VERSION 5.7 ;
  NOWIREEXTENSIONATPIN ON ;
  DIVIDERCHAR "/" ;
  BUSBITCHARS "[]" ;
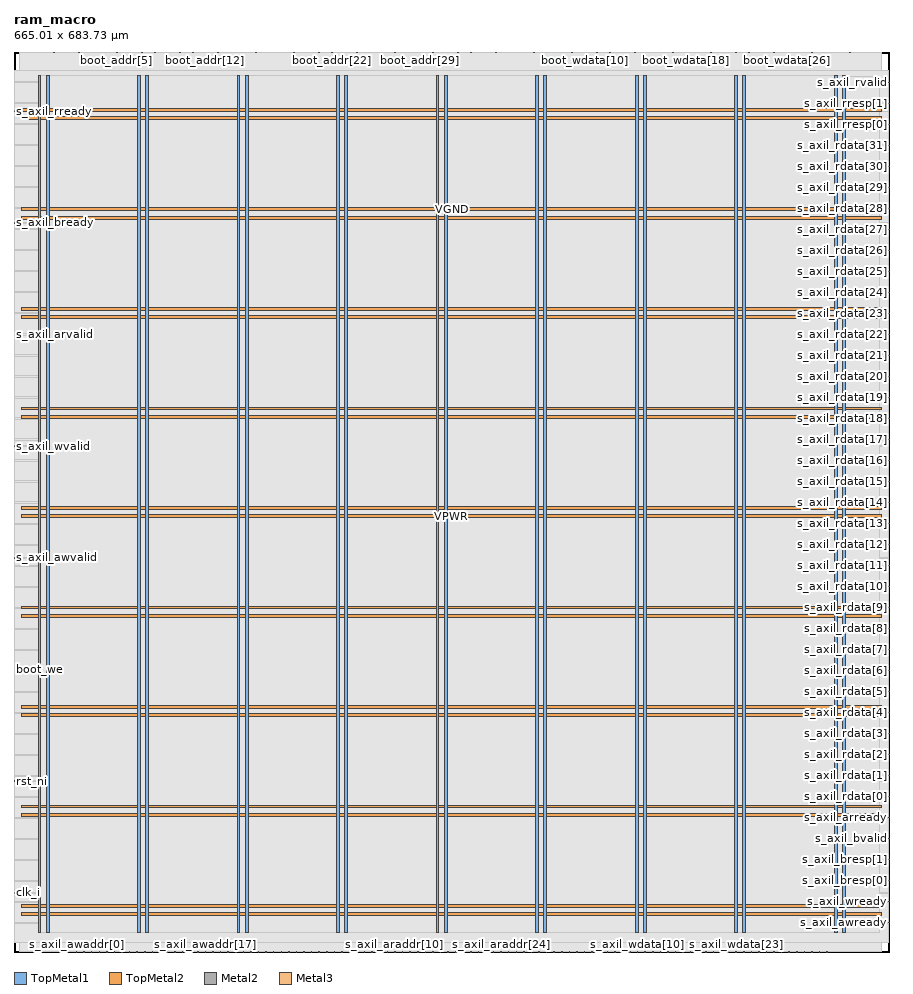
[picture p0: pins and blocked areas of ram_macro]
MACRO ram_macro
  CLASS BLOCK ;
  FOREIGN ram_macro ;
  ORIGIN 0.000 0.000 ;
  SIZE 665.010 BY 683.730 ;
  PIN VGND
    DIRECTION INOUT ;
    USE GROUND ;
    PORT
      LAYER TopMetal1 ;
        RECT 24.460 14.490 26.660 665.910 ;
    END
    PORT
      LAYER TopMetal1 ;
        RECT 100.060 14.490 102.260 665.910 ;
    END
    PORT
      LAYER TopMetal1 ;
        RECT 175.660 14.490 177.860 665.910 ;
    END
    PORT
      LAYER TopMetal1 ;
        RECT 251.260 14.490 253.460 665.910 ;
    END
    PORT
      LAYER TopMetal1 ;
        RECT 326.860 14.490 329.060 665.910 ;
    END
    PORT
      LAYER TopMetal1 ;
        RECT 402.460 14.490 404.660 665.910 ;
    END
    PORT
      LAYER TopMetal1 ;
        RECT 478.060 14.490 480.260 665.910 ;
    END
    PORT
      LAYER TopMetal1 ;
        RECT 553.660 14.490 555.860 665.910 ;
    END
    PORT
      LAYER TopMetal1 ;
        RECT 629.260 14.490 631.460 665.910 ;
    END
    PORT
      LAYER TopMetal2 ;
        RECT 5.760 33.820 659.040 36.020 ;
    END
    PORT
      LAYER TopMetal2 ;
        RECT 5.760 109.420 659.040 111.620 ;
    END
    PORT
      LAYER TopMetal2 ;
        RECT 5.760 185.020 659.040 187.220 ;
    END
    PORT
      LAYER TopMetal2 ;
        RECT 5.760 260.620 659.040 262.820 ;
    END
    PORT
      LAYER TopMetal2 ;
        RECT 5.760 336.220 659.040 338.420 ;
    END
    PORT
      LAYER TopMetal2 ;
        RECT 5.760 411.820 659.040 414.020 ;
    END
    PORT
      LAYER TopMetal2 ;
        RECT 5.760 487.420 659.040 489.620 ;
    END
    PORT
      LAYER TopMetal2 ;
        RECT 5.760 563.020 659.040 565.220 ;
    END
    PORT
      LAYER TopMetal2 ;
        RECT 5.760 638.620 659.040 640.820 ;
    END
  END VGND
  PIN VPWR
    DIRECTION INOUT ;
    USE POWER ;
    PORT
      LAYER TopMetal1 ;
        RECT 18.260 14.900 20.460 665.500 ;
    END
    PORT
      LAYER TopMetal1 ;
        RECT 93.860 14.900 96.060 665.500 ;
    END
    PORT
      LAYER TopMetal1 ;
        RECT 169.460 14.900 171.660 665.500 ;
    END
    PORT
      LAYER TopMetal1 ;
        RECT 245.060 14.900 247.260 665.500 ;
    END
    PORT
      LAYER TopMetal1 ;
        RECT 320.660 14.900 322.860 665.500 ;
    END
    PORT
      LAYER TopMetal1 ;
        RECT 396.260 14.900 398.460 665.500 ;
    END
    PORT
      LAYER TopMetal1 ;
        RECT 471.860 14.900 474.060 665.500 ;
    END
    PORT
      LAYER TopMetal1 ;
        RECT 547.460 14.900 549.660 665.500 ;
    END
    PORT
      LAYER TopMetal1 ;
        RECT 623.060 14.900 625.260 665.500 ;
    END
    PORT
      LAYER TopMetal2 ;
        RECT 5.760 27.620 659.040 29.820 ;
    END
    PORT
      LAYER TopMetal2 ;
        RECT 5.760 103.220 659.040 105.420 ;
    END
    PORT
      LAYER TopMetal2 ;
        RECT 5.760 178.820 659.040 181.020 ;
    END
    PORT
      LAYER TopMetal2 ;
        RECT 5.760 254.420 659.040 256.620 ;
    END
    PORT
      LAYER TopMetal2 ;
        RECT 5.760 330.020 659.040 332.220 ;
    END
    PORT
      LAYER TopMetal2 ;
        RECT 5.760 405.620 659.040 407.820 ;
    END
    PORT
      LAYER TopMetal2 ;
        RECT 5.760 481.220 659.040 483.420 ;
    END
    PORT
      LAYER TopMetal2 ;
        RECT 5.760 556.820 659.040 559.020 ;
    END
    PORT
      LAYER TopMetal2 ;
        RECT 5.760 632.420 659.040 634.620 ;
    END
  END VPWR
  PIN boot_addr[0]
    DIRECTION INPUT ;
    USE SIGNAL ;
    PORT
      LAYER Metal2 ;
        RECT 30.040 683.330 30.440 683.730 ;
    END
  END boot_addr[0]
  PIN boot_addr[10]
    DIRECTION INPUT ;
    USE SIGNAL ;
    ANTENNAGATEAREA 0.180700 ;
    PORT
      LAYER Metal2 ;
        RECT 126.040 683.330 126.440 683.730 ;
    END
  END boot_addr[10]
  PIN boot_addr[11]
    DIRECTION INPUT ;
    USE SIGNAL ;
    ANTENNAGATEAREA 0.180700 ;
    PORT
      LAYER Metal2 ;
        RECT 135.640 683.330 136.040 683.730 ;
    END
  END boot_addr[11]
  PIN boot_addr[12]
    DIRECTION INPUT ;
    USE SIGNAL ;
    PORT
      LAYER Metal2 ;
        RECT 145.240 683.330 145.640 683.730 ;
    END
  END boot_addr[12]
  PIN boot_addr[13]
    DIRECTION INPUT ;
    USE SIGNAL ;
    PORT
      LAYER Metal2 ;
        RECT 154.840 683.330 155.240 683.730 ;
    END
  END boot_addr[13]
  PIN boot_addr[14]
    DIRECTION INPUT ;
    USE SIGNAL ;
    PORT
      LAYER Metal2 ;
        RECT 164.440 683.330 164.840 683.730 ;
    END
  END boot_addr[14]
  PIN boot_addr[15]
    DIRECTION INPUT ;
    USE SIGNAL ;
    PORT
      LAYER Metal2 ;
        RECT 174.040 683.330 174.440 683.730 ;
    END
  END boot_addr[15]
  PIN boot_addr[16]
    DIRECTION INPUT ;
    USE SIGNAL ;
    PORT
      LAYER Metal2 ;
        RECT 183.640 683.330 184.040 683.730 ;
    END
  END boot_addr[16]
  PIN boot_addr[17]
    DIRECTION INPUT ;
    USE SIGNAL ;
    PORT
      LAYER Metal2 ;
        RECT 193.240 683.330 193.640 683.730 ;
    END
  END boot_addr[17]
  PIN boot_addr[18]
    DIRECTION INPUT ;
    USE SIGNAL ;
    PORT
      LAYER Metal2 ;
        RECT 202.840 683.330 203.240 683.730 ;
    END
  END boot_addr[18]
  PIN boot_addr[19]
    DIRECTION INPUT ;
    USE SIGNAL ;
    PORT
      LAYER Metal2 ;
        RECT 212.440 683.330 212.840 683.730 ;
    END
  END boot_addr[19]
  PIN boot_addr[1]
    DIRECTION INPUT ;
    USE SIGNAL ;
    PORT
      LAYER Metal2 ;
        RECT 39.640 683.330 40.040 683.730 ;
    END
  END boot_addr[1]
  PIN boot_addr[20]
    DIRECTION INPUT ;
    USE SIGNAL ;
    PORT
      LAYER Metal2 ;
        RECT 222.040 683.330 222.440 683.730 ;
    END
  END boot_addr[20]
  PIN boot_addr[21]
    DIRECTION INPUT ;
    USE SIGNAL ;
    PORT
      LAYER Metal2 ;
        RECT 231.640 683.330 232.040 683.730 ;
    END
  END boot_addr[21]
  PIN boot_addr[22]
    DIRECTION INPUT ;
    USE SIGNAL ;
    PORT
      LAYER Metal2 ;
        RECT 241.240 683.330 241.640 683.730 ;
    END
  END boot_addr[22]
  PIN boot_addr[23]
    DIRECTION INPUT ;
    USE SIGNAL ;
    PORT
      LAYER Metal2 ;
        RECT 250.840 683.330 251.240 683.730 ;
    END
  END boot_addr[23]
  PIN boot_addr[24]
    DIRECTION INPUT ;
    USE SIGNAL ;
    PORT
      LAYER Metal2 ;
        RECT 260.440 683.330 260.840 683.730 ;
    END
  END boot_addr[24]
  PIN boot_addr[25]
    DIRECTION INPUT ;
    USE SIGNAL ;
    PORT
      LAYER Metal2 ;
        RECT 270.040 683.330 270.440 683.730 ;
    END
  END boot_addr[25]
  PIN boot_addr[26]
    DIRECTION INPUT ;
    USE SIGNAL ;
    PORT
      LAYER Metal2 ;
        RECT 279.640 683.330 280.040 683.730 ;
    END
  END boot_addr[26]
  PIN boot_addr[27]
    DIRECTION INPUT ;
    USE SIGNAL ;
    PORT
      LAYER Metal2 ;
        RECT 289.240 683.330 289.640 683.730 ;
    END
  END boot_addr[27]
  PIN boot_addr[28]
    DIRECTION INPUT ;
    USE SIGNAL ;
    PORT
      LAYER Metal2 ;
        RECT 298.840 683.330 299.240 683.730 ;
    END
  END boot_addr[28]
  PIN boot_addr[29]
    DIRECTION INPUT ;
    USE SIGNAL ;
    PORT
      LAYER Metal2 ;
        RECT 308.440 683.330 308.840 683.730 ;
    END
  END boot_addr[29]
  PIN boot_addr[2]
    DIRECTION INPUT ;
    USE SIGNAL ;
    ANTENNAGATEAREA 0.180700 ;
    PORT
      LAYER Metal2 ;
        RECT 49.240 683.330 49.640 683.730 ;
    END
  END boot_addr[2]
  PIN boot_addr[30]
    DIRECTION INPUT ;
    USE SIGNAL ;
    PORT
      LAYER Metal2 ;
        RECT 318.040 683.330 318.440 683.730 ;
    END
  END boot_addr[30]
  PIN boot_addr[31]
    DIRECTION INPUT ;
    USE SIGNAL ;
    PORT
      LAYER Metal2 ;
        RECT 327.640 683.330 328.040 683.730 ;
    END
  END boot_addr[31]
  PIN boot_addr[3]
    DIRECTION INPUT ;
    USE SIGNAL ;
    ANTENNAGATEAREA 0.180700 ;
    PORT
      LAYER Metal2 ;
        RECT 58.840 683.330 59.240 683.730 ;
    END
  END boot_addr[3]
  PIN boot_addr[4]
    DIRECTION INPUT ;
    USE SIGNAL ;
    ANTENNAGATEAREA 0.180700 ;
    PORT
      LAYER Metal2 ;
        RECT 68.440 683.330 68.840 683.730 ;
    END
  END boot_addr[4]
  PIN boot_addr[5]
    DIRECTION INPUT ;
    USE SIGNAL ;
    ANTENNAGATEAREA 0.180700 ;
    PORT
      LAYER Metal2 ;
        RECT 78.040 683.330 78.440 683.730 ;
    END
  END boot_addr[5]
  PIN boot_addr[6]
    DIRECTION INPUT ;
    USE SIGNAL ;
    ANTENNAGATEAREA 0.180700 ;
    PORT
      LAYER Metal2 ;
        RECT 87.640 683.330 88.040 683.730 ;
    END
  END boot_addr[6]
  PIN boot_addr[7]
    DIRECTION INPUT ;
    USE SIGNAL ;
    ANTENNAGATEAREA 0.180700 ;
    PORT
      LAYER Metal2 ;
        RECT 97.240 683.330 97.640 683.730 ;
    END
  END boot_addr[7]
  PIN boot_addr[8]
    DIRECTION INPUT ;
    USE SIGNAL ;
    ANTENNAGATEAREA 0.180700 ;
    PORT
      LAYER Metal2 ;
        RECT 106.840 683.330 107.240 683.730 ;
    END
  END boot_addr[8]
  PIN boot_addr[9]
    DIRECTION INPUT ;
    USE SIGNAL ;
    ANTENNAGATEAREA 0.180700 ;
    PORT
      LAYER Metal2 ;
        RECT 116.440 683.330 116.840 683.730 ;
    END
  END boot_addr[9]
  PIN boot_wdata[0]
    DIRECTION INPUT ;
    USE SIGNAL ;
    ANTENNAGATEAREA 0.109200 ;
    PORT
      LAYER Metal2 ;
        RECT 337.240 683.330 337.640 683.730 ;
    END
  END boot_wdata[0]
  PIN boot_wdata[10]
    DIRECTION INPUT ;
    USE SIGNAL ;
    ANTENNAGATEAREA 0.109200 ;
    PORT
      LAYER Metal2 ;
        RECT 433.240 683.330 433.640 683.730 ;
    END
  END boot_wdata[10]
  PIN boot_wdata[11]
    DIRECTION INPUT ;
    USE SIGNAL ;
    ANTENNAGATEAREA 0.109200 ;
    PORT
      LAYER Metal2 ;
        RECT 442.840 683.330 443.240 683.730 ;
    END
  END boot_wdata[11]
  PIN boot_wdata[12]
    DIRECTION INPUT ;
    USE SIGNAL ;
    ANTENNAGATEAREA 0.109200 ;
    PORT
      LAYER Metal2 ;
        RECT 452.440 683.330 452.840 683.730 ;
    END
  END boot_wdata[12]
  PIN boot_wdata[13]
    DIRECTION INPUT ;
    USE SIGNAL ;
    ANTENNAGATEAREA 0.109200 ;
    PORT
      LAYER Metal2 ;
        RECT 462.040 683.330 462.440 683.730 ;
    END
  END boot_wdata[13]
  PIN boot_wdata[14]
    DIRECTION INPUT ;
    USE SIGNAL ;
    ANTENNAGATEAREA 0.109200 ;
    PORT
      LAYER Metal2 ;
        RECT 471.640 683.330 472.040 683.730 ;
    END
  END boot_wdata[14]
  PIN boot_wdata[15]
    DIRECTION INPUT ;
    USE SIGNAL ;
    ANTENNAGATEAREA 0.109200 ;
    PORT
      LAYER Metal2 ;
        RECT 481.240 683.330 481.640 683.730 ;
    END
  END boot_wdata[15]
  PIN boot_wdata[16]
    DIRECTION INPUT ;
    USE SIGNAL ;
    ANTENNAGATEAREA 0.109200 ;
    PORT
      LAYER Metal2 ;
        RECT 490.840 683.330 491.240 683.730 ;
    END
  END boot_wdata[16]
  PIN boot_wdata[17]
    DIRECTION INPUT ;
    USE SIGNAL ;
    ANTENNAGATEAREA 0.109200 ;
    PORT
      LAYER Metal2 ;
        RECT 500.440 683.330 500.840 683.730 ;
    END
  END boot_wdata[17]
  PIN boot_wdata[18]
    DIRECTION INPUT ;
    USE SIGNAL ;
    ANTENNAGATEAREA 0.109200 ;
    PORT
      LAYER Metal2 ;
        RECT 510.040 683.330 510.440 683.730 ;
    END
  END boot_wdata[18]
  PIN boot_wdata[19]
    DIRECTION INPUT ;
    USE SIGNAL ;
    ANTENNAGATEAREA 0.109200 ;
    PORT
      LAYER Metal2 ;
        RECT 519.640 683.330 520.040 683.730 ;
    END
  END boot_wdata[19]
  PIN boot_wdata[1]
    DIRECTION INPUT ;
    USE SIGNAL ;
    ANTENNAGATEAREA 0.109200 ;
    PORT
      LAYER Metal2 ;
        RECT 346.840 683.330 347.240 683.730 ;
    END
  END boot_wdata[1]
  PIN boot_wdata[20]
    DIRECTION INPUT ;
    USE SIGNAL ;
    ANTENNAGATEAREA 0.109200 ;
    PORT
      LAYER Metal2 ;
        RECT 529.240 683.330 529.640 683.730 ;
    END
  END boot_wdata[20]
  PIN boot_wdata[21]
    DIRECTION INPUT ;
    USE SIGNAL ;
    ANTENNAGATEAREA 0.109200 ;
    PORT
      LAYER Metal2 ;
        RECT 538.840 683.330 539.240 683.730 ;
    END
  END boot_wdata[21]
  PIN boot_wdata[22]
    DIRECTION INPUT ;
    USE SIGNAL ;
    ANTENNAGATEAREA 0.109200 ;
    PORT
      LAYER Metal2 ;
        RECT 548.440 683.330 548.840 683.730 ;
    END
  END boot_wdata[22]
  PIN boot_wdata[23]
    DIRECTION INPUT ;
    USE SIGNAL ;
    ANTENNAGATEAREA 0.109200 ;
    PORT
      LAYER Metal2 ;
        RECT 558.040 683.330 558.440 683.730 ;
    END
  END boot_wdata[23]
  PIN boot_wdata[24]
    DIRECTION INPUT ;
    USE SIGNAL ;
    ANTENNAGATEAREA 0.109200 ;
    PORT
      LAYER Metal2 ;
        RECT 567.640 683.330 568.040 683.730 ;
    END
  END boot_wdata[24]
  PIN boot_wdata[25]
    DIRECTION INPUT ;
    USE SIGNAL ;
    ANTENNAGATEAREA 0.109200 ;
    PORT
      LAYER Metal2 ;
        RECT 577.240 683.330 577.640 683.730 ;
    END
  END boot_wdata[25]
  PIN boot_wdata[26]
    DIRECTION INPUT ;
    USE SIGNAL ;
    ANTENNAGATEAREA 0.109200 ;
    PORT
      LAYER Metal2 ;
        RECT 586.840 683.330 587.240 683.730 ;
    END
  END boot_wdata[26]
  PIN boot_wdata[27]
    DIRECTION INPUT ;
    USE SIGNAL ;
    ANTENNAGATEAREA 0.109200 ;
    PORT
      LAYER Metal2 ;
        RECT 596.440 683.330 596.840 683.730 ;
    END
  END boot_wdata[27]
  PIN boot_wdata[28]
    DIRECTION INPUT ;
    USE SIGNAL ;
    ANTENNAGATEAREA 0.109200 ;
    PORT
      LAYER Metal2 ;
        RECT 606.040 683.330 606.440 683.730 ;
    END
  END boot_wdata[28]
  PIN boot_wdata[29]
    DIRECTION INPUT ;
    USE SIGNAL ;
    ANTENNAGATEAREA 0.109200 ;
    PORT
      LAYER Metal2 ;
        RECT 615.640 683.330 616.040 683.730 ;
    END
  END boot_wdata[29]
  PIN boot_wdata[2]
    DIRECTION INPUT ;
    USE SIGNAL ;
    ANTENNAGATEAREA 0.109200 ;
    PORT
      LAYER Metal2 ;
        RECT 356.440 683.330 356.840 683.730 ;
    END
  END boot_wdata[2]
  PIN boot_wdata[30]
    DIRECTION INPUT ;
    USE SIGNAL ;
    ANTENNAGATEAREA 0.109200 ;
    PORT
      LAYER Metal2 ;
        RECT 625.240 683.330 625.640 683.730 ;
    END
  END boot_wdata[30]
  PIN boot_wdata[31]
    DIRECTION INPUT ;
    USE SIGNAL ;
    ANTENNAGATEAREA 0.109200 ;
    PORT
      LAYER Metal2 ;
        RECT 634.840 683.330 635.240 683.730 ;
    END
  END boot_wdata[31]
  PIN boot_wdata[3]
    DIRECTION INPUT ;
    USE SIGNAL ;
    ANTENNAGATEAREA 0.109200 ;
    PORT
      LAYER Metal2 ;
        RECT 366.040 683.330 366.440 683.730 ;
    END
  END boot_wdata[3]
  PIN boot_wdata[4]
    DIRECTION INPUT ;
    USE SIGNAL ;
    ANTENNAGATEAREA 0.109200 ;
    PORT
      LAYER Metal2 ;
        RECT 375.640 683.330 376.040 683.730 ;
    END
  END boot_wdata[4]
  PIN boot_wdata[5]
    DIRECTION INPUT ;
    USE SIGNAL ;
    ANTENNAGATEAREA 0.109200 ;
    PORT
      LAYER Metal2 ;
        RECT 385.240 683.330 385.640 683.730 ;
    END
  END boot_wdata[5]
  PIN boot_wdata[6]
    DIRECTION INPUT ;
    USE SIGNAL ;
    ANTENNAGATEAREA 0.109200 ;
    PORT
      LAYER Metal2 ;
        RECT 394.840 683.330 395.240 683.730 ;
    END
  END boot_wdata[6]
  PIN boot_wdata[7]
    DIRECTION INPUT ;
    USE SIGNAL ;
    ANTENNAGATEAREA 0.109200 ;
    PORT
      LAYER Metal2 ;
        RECT 404.440 683.330 404.840 683.730 ;
    END
  END boot_wdata[7]
  PIN boot_wdata[8]
    DIRECTION INPUT ;
    USE SIGNAL ;
    ANTENNAGATEAREA 0.109200 ;
    PORT
      LAYER Metal2 ;
        RECT 414.040 683.330 414.440 683.730 ;
    END
  END boot_wdata[8]
  PIN boot_wdata[9]
    DIRECTION INPUT ;
    USE SIGNAL ;
    ANTENNAGATEAREA 0.109200 ;
    PORT
      LAYER Metal2 ;
        RECT 423.640 683.330 424.040 683.730 ;
    END
  END boot_wdata[9]
  PIN boot_we
    DIRECTION INPUT ;
    USE SIGNAL ;
    ANTENNAGATEAREA 0.109200 ;
    PORT
      LAYER Metal3 ;
        RECT 0.000 214.420 0.400 214.820 ;
    END
  END boot_we
  PIN clk_i
    DIRECTION INPUT ;
    USE SIGNAL ;
    ANTENNAGATEAREA 2.901600 ;
    PORT
      LAYER Metal3 ;
        RECT 0.000 44.740 0.400 45.140 ;
    END
  END clk_i
  PIN rst_ni
    DIRECTION INPUT ;
    USE SIGNAL ;
    ANTENNAGATEAREA 0.180700 ;
    PORT
      LAYER Metal3 ;
        RECT 0.000 129.580 0.400 129.980 ;
    END
  END rst_ni
  PIN s_axil_araddr[0]
    DIRECTION INPUT ;
    USE SIGNAL ;
    ANTENNAGATEAREA 0.180700 ;
    PORT
      LAYER Metal2 ;
        RECT 231.640 0.000 232.040 0.400 ;
    END
  END s_axil_araddr[0]
  PIN s_axil_araddr[10]
    DIRECTION INPUT ;
    USE SIGNAL ;
    ANTENNAGATEAREA 0.180700 ;
    PORT
      LAYER Metal2 ;
        RECT 289.240 0.000 289.640 0.400 ;
    END
  END s_axil_araddr[10]
  PIN s_axil_araddr[11]
    DIRECTION INPUT ;
    USE SIGNAL ;
    ANTENNAGATEAREA 0.180700 ;
    PORT
      LAYER Metal2 ;
        RECT 295.000 0.000 295.400 0.400 ;
    END
  END s_axil_araddr[11]
  PIN s_axil_araddr[12]
    DIRECTION INPUT ;
    USE SIGNAL ;
    ANTENNAGATEAREA 0.180700 ;
    PORT
      LAYER Metal2 ;
        RECT 300.760 0.000 301.160 0.400 ;
    END
  END s_axil_araddr[12]
  PIN s_axil_araddr[13]
    DIRECTION INPUT ;
    USE SIGNAL ;
    ANTENNAGATEAREA 0.180700 ;
    PORT
      LAYER Metal2 ;
        RECT 306.520 0.000 306.920 0.400 ;
    END
  END s_axil_araddr[13]
  PIN s_axil_araddr[14]
    DIRECTION INPUT ;
    USE SIGNAL ;
    ANTENNAGATEAREA 0.180700 ;
    PORT
      LAYER Metal2 ;
        RECT 312.280 0.000 312.680 0.400 ;
    END
  END s_axil_araddr[14]
  PIN s_axil_araddr[15]
    DIRECTION INPUT ;
    USE SIGNAL ;
    ANTENNAGATEAREA 0.180700 ;
    PORT
      LAYER Metal2 ;
        RECT 318.040 0.000 318.440 0.400 ;
    END
  END s_axil_araddr[15]
  PIN s_axil_araddr[16]
    DIRECTION INPUT ;
    USE SIGNAL ;
    ANTENNAGATEAREA 0.180700 ;
    PORT
      LAYER Metal2 ;
        RECT 323.800 0.000 324.200 0.400 ;
    END
  END s_axil_araddr[16]
  PIN s_axil_araddr[17]
    DIRECTION INPUT ;
    USE SIGNAL ;
    ANTENNAGATEAREA 0.180700 ;
    PORT
      LAYER Metal2 ;
        RECT 329.560 0.000 329.960 0.400 ;
    END
  END s_axil_araddr[17]
  PIN s_axil_araddr[18]
    DIRECTION INPUT ;
    USE SIGNAL ;
    ANTENNAGATEAREA 0.180700 ;
    PORT
      LAYER Metal2 ;
        RECT 335.320 0.000 335.720 0.400 ;
    END
  END s_axil_araddr[18]
  PIN s_axil_araddr[19]
    DIRECTION INPUT ;
    USE SIGNAL ;
    ANTENNAGATEAREA 0.180700 ;
    PORT
      LAYER Metal2 ;
        RECT 341.080 0.000 341.480 0.400 ;
    END
  END s_axil_araddr[19]
  PIN s_axil_araddr[1]
    DIRECTION INPUT ;
    USE SIGNAL ;
    ANTENNAGATEAREA 0.180700 ;
    PORT
      LAYER Metal2 ;
        RECT 237.400 0.000 237.800 0.400 ;
    END
  END s_axil_araddr[1]
  PIN s_axil_araddr[20]
    DIRECTION INPUT ;
    USE SIGNAL ;
    ANTENNAGATEAREA 0.180700 ;
    PORT
      LAYER Metal2 ;
        RECT 346.840 0.000 347.240 0.400 ;
    END
  END s_axil_araddr[20]
  PIN s_axil_araddr[21]
    DIRECTION INPUT ;
    USE SIGNAL ;
    ANTENNAGATEAREA 0.180700 ;
    PORT
      LAYER Metal2 ;
        RECT 352.600 0.000 353.000 0.400 ;
    END
  END s_axil_araddr[21]
  PIN s_axil_araddr[22]
    DIRECTION INPUT ;
    USE SIGNAL ;
    ANTENNAGATEAREA 0.180700 ;
    PORT
      LAYER Metal2 ;
        RECT 358.360 0.000 358.760 0.400 ;
    END
  END s_axil_araddr[22]
  PIN s_axil_araddr[23]
    DIRECTION INPUT ;
    USE SIGNAL ;
    ANTENNAGATEAREA 0.180700 ;
    PORT
      LAYER Metal2 ;
        RECT 364.120 0.000 364.520 0.400 ;
    END
  END s_axil_araddr[23]
  PIN s_axil_araddr[24]
    DIRECTION INPUT ;
    USE SIGNAL ;
    ANTENNAGATEAREA 0.180700 ;
    PORT
      LAYER Metal2 ;
        RECT 369.880 0.000 370.280 0.400 ;
    END
  END s_axil_araddr[24]
  PIN s_axil_araddr[25]
    DIRECTION INPUT ;
    USE SIGNAL ;
    ANTENNAGATEAREA 0.180700 ;
    PORT
      LAYER Metal2 ;
        RECT 375.640 0.000 376.040 0.400 ;
    END
  END s_axil_araddr[25]
  PIN s_axil_araddr[26]
    DIRECTION INPUT ;
    USE SIGNAL ;
    ANTENNAGATEAREA 0.180700 ;
    PORT
      LAYER Metal2 ;
        RECT 381.400 0.000 381.800 0.400 ;
    END
  END s_axil_araddr[26]
  PIN s_axil_araddr[27]
    DIRECTION INPUT ;
    USE SIGNAL ;
    ANTENNAGATEAREA 0.180700 ;
    PORT
      LAYER Metal2 ;
        RECT 387.160 0.000 387.560 0.400 ;
    END
  END s_axil_araddr[27]
  PIN s_axil_araddr[28]
    DIRECTION INPUT ;
    USE SIGNAL ;
    ANTENNAGATEAREA 0.180700 ;
    PORT
      LAYER Metal2 ;
        RECT 392.920 0.000 393.320 0.400 ;
    END
  END s_axil_araddr[28]
  PIN s_axil_araddr[29]
    DIRECTION INPUT ;
    USE SIGNAL ;
    ANTENNAGATEAREA 0.180700 ;
    PORT
      LAYER Metal2 ;
        RECT 398.680 0.000 399.080 0.400 ;
    END
  END s_axil_araddr[29]
  PIN s_axil_araddr[2]
    DIRECTION INPUT ;
    USE SIGNAL ;
    ANTENNAGATEAREA 0.180700 ;
    PORT
      LAYER Metal2 ;
        RECT 243.160 0.000 243.560 0.400 ;
    END
  END s_axil_araddr[2]
  PIN s_axil_araddr[30]
    DIRECTION INPUT ;
    USE SIGNAL ;
    ANTENNAGATEAREA 0.180700 ;
    PORT
      LAYER Metal2 ;
        RECT 404.440 0.000 404.840 0.400 ;
    END
  END s_axil_araddr[30]
  PIN s_axil_araddr[31]
    DIRECTION INPUT ;
    USE SIGNAL ;
    ANTENNAGATEAREA 0.180700 ;
    PORT
      LAYER Metal2 ;
        RECT 410.200 0.000 410.600 0.400 ;
    END
  END s_axil_araddr[31]
  PIN s_axil_araddr[3]
    DIRECTION INPUT ;
    USE SIGNAL ;
    ANTENNAGATEAREA 0.180700 ;
    PORT
      LAYER Metal2 ;
        RECT 248.920 0.000 249.320 0.400 ;
    END
  END s_axil_araddr[3]
  PIN s_axil_araddr[4]
    DIRECTION INPUT ;
    USE SIGNAL ;
    ANTENNAGATEAREA 0.180700 ;
    PORT
      LAYER Metal2 ;
        RECT 254.680 0.000 255.080 0.400 ;
    END
  END s_axil_araddr[4]
  PIN s_axil_araddr[5]
    DIRECTION INPUT ;
    USE SIGNAL ;
    ANTENNAGATEAREA 0.180700 ;
    PORT
      LAYER Metal2 ;
        RECT 260.440 0.000 260.840 0.400 ;
    END
  END s_axil_araddr[5]
  PIN s_axil_araddr[6]
    DIRECTION INPUT ;
    USE SIGNAL ;
    ANTENNAGATEAREA 0.180700 ;
    PORT
      LAYER Metal2 ;
        RECT 266.200 0.000 266.600 0.400 ;
    END
  END s_axil_araddr[6]
  PIN s_axil_araddr[7]
    DIRECTION INPUT ;
    USE SIGNAL ;
    ANTENNAGATEAREA 0.180700 ;
    PORT
      LAYER Metal2 ;
        RECT 271.960 0.000 272.360 0.400 ;
    END
  END s_axil_araddr[7]
  PIN s_axil_araddr[8]
    DIRECTION INPUT ;
    USE SIGNAL ;
    ANTENNAGATEAREA 0.180700 ;
    PORT
      LAYER Metal2 ;
        RECT 277.720 0.000 278.120 0.400 ;
    END
  END s_axil_araddr[8]
  PIN s_axil_araddr[9]
    DIRECTION INPUT ;
    USE SIGNAL ;
    ANTENNAGATEAREA 0.180700 ;
    PORT
      LAYER Metal2 ;
        RECT 283.480 0.000 283.880 0.400 ;
    END
  END s_axil_araddr[9]
  PIN s_axil_arready
    DIRECTION OUTPUT ;
    USE SIGNAL ;
    ANTENNADIFFAREA 0.708600 ;
    PORT
      LAYER Metal3 ;
        RECT 664.610 101.860 665.010 102.260 ;
    END
  END s_axil_arready
  PIN s_axil_arvalid
    DIRECTION INPUT ;
    USE SIGNAL ;
    ANTENNAGATEAREA 0.180700 ;
    PORT
      LAYER Metal3 ;
        RECT 0.000 468.940 0.400 469.340 ;
    END
  END s_axil_arvalid
  PIN s_axil_awaddr[0]
    DIRECTION INPUT ;
    USE SIGNAL ;
    ANTENNAGATEAREA 0.180700 ;
    PORT
      LAYER Metal2 ;
        RECT 47.320 0.000 47.720 0.400 ;
    END
  END s_axil_awaddr[0]
  PIN s_axil_awaddr[10]
    DIRECTION INPUT ;
    USE SIGNAL ;
    ANTENNAGATEAREA 0.180700 ;
    PORT
      LAYER Metal2 ;
        RECT 104.920 0.000 105.320 0.400 ;
    END
  END s_axil_awaddr[10]
  PIN s_axil_awaddr[11]
    DIRECTION INPUT ;
    USE SIGNAL ;
    ANTENNAGATEAREA 0.180700 ;
    PORT
      LAYER Metal2 ;
        RECT 110.680 0.000 111.080 0.400 ;
    END
  END s_axil_awaddr[11]
  PIN s_axil_awaddr[12]
    DIRECTION INPUT ;
    USE SIGNAL ;
    ANTENNAGATEAREA 0.180700 ;
    PORT
      LAYER Metal2 ;
        RECT 116.440 0.000 116.840 0.400 ;
    END
  END s_axil_awaddr[12]
  PIN s_axil_awaddr[13]
    DIRECTION INPUT ;
    USE SIGNAL ;
    ANTENNAGATEAREA 0.180700 ;
    PORT
      LAYER Metal2 ;
        RECT 122.200 0.000 122.600 0.400 ;
    END
  END s_axil_awaddr[13]
  PIN s_axil_awaddr[14]
    DIRECTION INPUT ;
    USE SIGNAL ;
    ANTENNAGATEAREA 0.180700 ;
    PORT
      LAYER Metal2 ;
        RECT 127.960 0.000 128.360 0.400 ;
    END
  END s_axil_awaddr[14]
  PIN s_axil_awaddr[15]
    DIRECTION INPUT ;
    USE SIGNAL ;
    ANTENNAGATEAREA 0.180700 ;
    PORT
      LAYER Metal2 ;
        RECT 133.720 0.000 134.120 0.400 ;
    END
  END s_axil_awaddr[15]
  PIN s_axil_awaddr[16]
    DIRECTION INPUT ;
    USE SIGNAL ;
    ANTENNAGATEAREA 0.180700 ;
    PORT
      LAYER Metal2 ;
        RECT 139.480 0.000 139.880 0.400 ;
    END
  END s_axil_awaddr[16]
  PIN s_axil_awaddr[17]
    DIRECTION INPUT ;
    USE SIGNAL ;
    ANTENNAGATEAREA 0.180700 ;
    PORT
      LAYER Metal2 ;
        RECT 145.240 0.000 145.640 0.400 ;
    END
  END s_axil_awaddr[17]
  PIN s_axil_awaddr[18]
    DIRECTION INPUT ;
    USE SIGNAL ;
    ANTENNAGATEAREA 0.180700 ;
    PORT
      LAYER Metal2 ;
        RECT 151.000 0.000 151.400 0.400 ;
    END
  END s_axil_awaddr[18]
  PIN s_axil_awaddr[19]
    DIRECTION INPUT ;
    USE SIGNAL ;
    ANTENNAGATEAREA 0.180700 ;
    PORT
      LAYER Metal2 ;
        RECT 156.760 0.000 157.160 0.400 ;
    END
  END s_axil_awaddr[19]
  PIN s_axil_awaddr[1]
    DIRECTION INPUT ;
    USE SIGNAL ;
    ANTENNAGATEAREA 0.180700 ;
    PORT
      LAYER Metal2 ;
        RECT 53.080 0.000 53.480 0.400 ;
    END
  END s_axil_awaddr[1]
  PIN s_axil_awaddr[20]
    DIRECTION INPUT ;
    USE SIGNAL ;
    ANTENNAGATEAREA 0.180700 ;
    PORT
      LAYER Metal2 ;
        RECT 162.520 0.000 162.920 0.400 ;
    END
  END s_axil_awaddr[20]
  PIN s_axil_awaddr[21]
    DIRECTION INPUT ;
    USE SIGNAL ;
    ANTENNAGATEAREA 0.180700 ;
    PORT
      LAYER Metal2 ;
        RECT 168.280 0.000 168.680 0.400 ;
    END
  END s_axil_awaddr[21]
  PIN s_axil_awaddr[22]
    DIRECTION INPUT ;
    USE SIGNAL ;
    ANTENNAGATEAREA 0.180700 ;
    PORT
      LAYER Metal2 ;
        RECT 174.040 0.000 174.440 0.400 ;
    END
  END s_axil_awaddr[22]
  PIN s_axil_awaddr[23]
    DIRECTION INPUT ;
    USE SIGNAL ;
    ANTENNAGATEAREA 0.180700 ;
    PORT
      LAYER Metal2 ;
        RECT 179.800 0.000 180.200 0.400 ;
    END
  END s_axil_awaddr[23]
  PIN s_axil_awaddr[24]
    DIRECTION INPUT ;
    USE SIGNAL ;
    ANTENNAGATEAREA 0.109200 ;
    PORT
      LAYER Metal2 ;
        RECT 185.560 0.000 185.960 0.400 ;
    END
  END s_axil_awaddr[24]
  PIN s_axil_awaddr[25]
    DIRECTION INPUT ;
    USE SIGNAL ;
    ANTENNAGATEAREA 0.180700 ;
    PORT
      LAYER Metal2 ;
        RECT 191.320 0.000 191.720 0.400 ;
    END
  END s_axil_awaddr[25]
  PIN s_axil_awaddr[26]
    DIRECTION INPUT ;
    USE SIGNAL ;
    ANTENNAGATEAREA 0.180700 ;
    PORT
      LAYER Metal2 ;
        RECT 197.080 0.000 197.480 0.400 ;
    END
  END s_axil_awaddr[26]
  PIN s_axil_awaddr[27]
    DIRECTION INPUT ;
    USE SIGNAL ;
    ANTENNAGATEAREA 0.180700 ;
    PORT
      LAYER Metal2 ;
        RECT 202.840 0.000 203.240 0.400 ;
    END
  END s_axil_awaddr[27]
  PIN s_axil_awaddr[28]
    DIRECTION INPUT ;
    USE SIGNAL ;
    ANTENNAGATEAREA 0.109200 ;
    PORT
      LAYER Metal2 ;
        RECT 208.600 0.000 209.000 0.400 ;
    END
  END s_axil_awaddr[28]
  PIN s_axil_awaddr[29]
    DIRECTION INPUT ;
    USE SIGNAL ;
    ANTENNAGATEAREA 0.180700 ;
    PORT
      LAYER Metal2 ;
        RECT 214.360 0.000 214.760 0.400 ;
    END
  END s_axil_awaddr[29]
  PIN s_axil_awaddr[2]
    DIRECTION INPUT ;
    USE SIGNAL ;
    ANTENNAGATEAREA 0.180700 ;
    PORT
      LAYER Metal2 ;
        RECT 58.840 0.000 59.240 0.400 ;
    END
  END s_axil_awaddr[2]
  PIN s_axil_awaddr[30]
    DIRECTION INPUT ;
    USE SIGNAL ;
    ANTENNAGATEAREA 0.180700 ;
    PORT
      LAYER Metal2 ;
        RECT 220.120 0.000 220.520 0.400 ;
    END
  END s_axil_awaddr[30]
  PIN s_axil_awaddr[31]
    DIRECTION INPUT ;
    USE SIGNAL ;
    ANTENNAGATEAREA 0.180700 ;
    PORT
      LAYER Metal2 ;
        RECT 225.880 0.000 226.280 0.400 ;
    END
  END s_axil_awaddr[31]
  PIN s_axil_awaddr[3]
    DIRECTION INPUT ;
    USE SIGNAL ;
    ANTENNAGATEAREA 0.180700 ;
    PORT
      LAYER Metal2 ;
        RECT 64.600 0.000 65.000 0.400 ;
    END
  END s_axil_awaddr[3]
  PIN s_axil_awaddr[4]
    DIRECTION INPUT ;
    USE SIGNAL ;
    ANTENNAGATEAREA 0.180700 ;
    PORT
      LAYER Metal2 ;
        RECT 70.360 0.000 70.760 0.400 ;
    END
  END s_axil_awaddr[4]
  PIN s_axil_awaddr[5]
    DIRECTION INPUT ;
    USE SIGNAL ;
    ANTENNAGATEAREA 0.180700 ;
    PORT
      LAYER Metal2 ;
        RECT 76.120 0.000 76.520 0.400 ;
    END
  END s_axil_awaddr[5]
  PIN s_axil_awaddr[6]
    DIRECTION INPUT ;
    USE SIGNAL ;
    ANTENNAGATEAREA 0.180700 ;
    PORT
      LAYER Metal2 ;
        RECT 81.880 0.000 82.280 0.400 ;
    END
  END s_axil_awaddr[6]
  PIN s_axil_awaddr[7]
    DIRECTION INPUT ;
    USE SIGNAL ;
    ANTENNAGATEAREA 0.180700 ;
    PORT
      LAYER Metal2 ;
        RECT 87.640 0.000 88.040 0.400 ;
    END
  END s_axil_awaddr[7]
  PIN s_axil_awaddr[8]
    DIRECTION INPUT ;
    USE SIGNAL ;
    ANTENNAGATEAREA 0.180700 ;
    PORT
      LAYER Metal2 ;
        RECT 93.400 0.000 93.800 0.400 ;
    END
  END s_axil_awaddr[8]
  PIN s_axil_awaddr[9]
    DIRECTION INPUT ;
    USE SIGNAL ;
    ANTENNAGATEAREA 0.180700 ;
    PORT
      LAYER Metal2 ;
        RECT 99.160 0.000 99.560 0.400 ;
    END
  END s_axil_awaddr[9]
  PIN s_axil_awready
    DIRECTION OUTPUT ;
    USE SIGNAL ;
    ANTENNADIFFAREA 0.708600 ;
    PORT
      LAYER Metal3 ;
        RECT 664.610 22.060 665.010 22.460 ;
    END
  END s_axil_awready
  PIN s_axil_awvalid
    DIRECTION INPUT ;
    USE SIGNAL ;
    ANTENNAGATEAREA 0.180700 ;
    PORT
      LAYER Metal3 ;
        RECT 0.000 299.260 0.400 299.660 ;
    END
  END s_axil_awvalid
  PIN s_axil_bready
    DIRECTION INPUT ;
    USE SIGNAL ;
    ANTENNAGATEAREA 0.180700 ;
    PORT
      LAYER Metal3 ;
        RECT 0.000 553.780 0.400 554.180 ;
    END
  END s_axil_bready
  PIN s_axil_bresp[0]
    DIRECTION OUTPUT ;
    USE SIGNAL ;
    ANTENNADIFFAREA 0.708600 ;
    PORT
      LAYER Metal3 ;
        RECT 664.610 53.980 665.010 54.380 ;
    END
  END s_axil_bresp[0]
  PIN s_axil_bresp[1]
    DIRECTION OUTPUT ;
    USE SIGNAL ;
    ANTENNADIFFAREA 0.708600 ;
    PORT
      LAYER Metal3 ;
        RECT 664.610 69.940 665.010 70.340 ;
    END
  END s_axil_bresp[1]
  PIN s_axil_bvalid
    DIRECTION OUTPUT ;
    USE SIGNAL ;
    ANTENNADIFFAREA 0.708600 ;
    PORT
      LAYER Metal3 ;
        RECT 664.610 85.900 665.010 86.300 ;
    END
  END s_axil_bvalid
  PIN s_axil_rdata[0]
    DIRECTION OUTPUT ;
    USE SIGNAL ;
    ANTENNADIFFAREA 0.708600 ;
    PORT
      LAYER Metal3 ;
        RECT 664.610 117.820 665.010 118.220 ;
    END
  END s_axil_rdata[0]
  PIN s_axil_rdata[10]
    DIRECTION OUTPUT ;
    USE SIGNAL ;
    ANTENNADIFFAREA 0.708600 ;
    PORT
      LAYER Metal3 ;
        RECT 664.610 277.420 665.010 277.820 ;
    END
  END s_axil_rdata[10]
  PIN s_axil_rdata[11]
    DIRECTION OUTPUT ;
    USE SIGNAL ;
    ANTENNADIFFAREA 0.708600 ;
    PORT
      LAYER Metal3 ;
        RECT 664.610 293.380 665.010 293.780 ;
    END
  END s_axil_rdata[11]
  PIN s_axil_rdata[12]
    DIRECTION OUTPUT ;
    USE SIGNAL ;
    ANTENNADIFFAREA 0.708600 ;
    PORT
      LAYER Metal3 ;
        RECT 664.610 309.340 665.010 309.740 ;
    END
  END s_axil_rdata[12]
  PIN s_axil_rdata[13]
    DIRECTION OUTPUT ;
    USE SIGNAL ;
    ANTENNADIFFAREA 0.708600 ;
    PORT
      LAYER Metal3 ;
        RECT 664.610 325.300 665.010 325.700 ;
    END
  END s_axil_rdata[13]
  PIN s_axil_rdata[14]
    DIRECTION OUTPUT ;
    USE SIGNAL ;
    ANTENNADIFFAREA 0.708600 ;
    PORT
      LAYER Metal3 ;
        RECT 664.610 341.260 665.010 341.660 ;
    END
  END s_axil_rdata[14]
  PIN s_axil_rdata[15]
    DIRECTION OUTPUT ;
    USE SIGNAL ;
    ANTENNADIFFAREA 0.708600 ;
    PORT
      LAYER Metal3 ;
        RECT 664.610 357.220 665.010 357.620 ;
    END
  END s_axil_rdata[15]
  PIN s_axil_rdata[16]
    DIRECTION OUTPUT ;
    USE SIGNAL ;
    ANTENNADIFFAREA 0.708600 ;
    PORT
      LAYER Metal3 ;
        RECT 664.610 373.180 665.010 373.580 ;
    END
  END s_axil_rdata[16]
  PIN s_axil_rdata[17]
    DIRECTION OUTPUT ;
    USE SIGNAL ;
    ANTENNADIFFAREA 0.708600 ;
    PORT
      LAYER Metal3 ;
        RECT 664.610 389.140 665.010 389.540 ;
    END
  END s_axil_rdata[17]
  PIN s_axil_rdata[18]
    DIRECTION OUTPUT ;
    USE SIGNAL ;
    ANTENNADIFFAREA 0.708600 ;
    PORT
      LAYER Metal3 ;
        RECT 664.610 405.100 665.010 405.500 ;
    END
  END s_axil_rdata[18]
  PIN s_axil_rdata[19]
    DIRECTION OUTPUT ;
    USE SIGNAL ;
    ANTENNADIFFAREA 0.708600 ;
    PORT
      LAYER Metal3 ;
        RECT 664.610 421.060 665.010 421.460 ;
    END
  END s_axil_rdata[19]
  PIN s_axil_rdata[1]
    DIRECTION OUTPUT ;
    USE SIGNAL ;
    ANTENNADIFFAREA 0.708600 ;
    PORT
      LAYER Metal3 ;
        RECT 664.610 133.780 665.010 134.180 ;
    END
  END s_axil_rdata[1]
  PIN s_axil_rdata[20]
    DIRECTION OUTPUT ;
    USE SIGNAL ;
    ANTENNADIFFAREA 0.708600 ;
    PORT
      LAYER Metal3 ;
        RECT 664.610 437.020 665.010 437.420 ;
    END
  END s_axil_rdata[20]
  PIN s_axil_rdata[21]
    DIRECTION OUTPUT ;
    USE SIGNAL ;
    ANTENNADIFFAREA 0.708600 ;
    PORT
      LAYER Metal3 ;
        RECT 664.610 452.980 665.010 453.380 ;
    END
  END s_axil_rdata[21]
  PIN s_axil_rdata[22]
    DIRECTION OUTPUT ;
    USE SIGNAL ;
    ANTENNADIFFAREA 0.708600 ;
    PORT
      LAYER Metal3 ;
        RECT 664.610 468.940 665.010 469.340 ;
    END
  END s_axil_rdata[22]
  PIN s_axil_rdata[23]
    DIRECTION OUTPUT ;
    USE SIGNAL ;
    ANTENNADIFFAREA 0.708600 ;
    PORT
      LAYER Metal3 ;
        RECT 664.610 484.900 665.010 485.300 ;
    END
  END s_axil_rdata[23]
  PIN s_axil_rdata[24]
    DIRECTION OUTPUT ;
    USE SIGNAL ;
    ANTENNADIFFAREA 0.708600 ;
    PORT
      LAYER Metal3 ;
        RECT 664.610 500.860 665.010 501.260 ;
    END
  END s_axil_rdata[24]
  PIN s_axil_rdata[25]
    DIRECTION OUTPUT ;
    USE SIGNAL ;
    ANTENNADIFFAREA 0.708600 ;
    PORT
      LAYER Metal3 ;
        RECT 664.610 516.820 665.010 517.220 ;
    END
  END s_axil_rdata[25]
  PIN s_axil_rdata[26]
    DIRECTION OUTPUT ;
    USE SIGNAL ;
    ANTENNADIFFAREA 0.708600 ;
    PORT
      LAYER Metal3 ;
        RECT 664.610 532.780 665.010 533.180 ;
    END
  END s_axil_rdata[26]
  PIN s_axil_rdata[27]
    DIRECTION OUTPUT ;
    USE SIGNAL ;
    ANTENNADIFFAREA 0.708600 ;
    PORT
      LAYER Metal3 ;
        RECT 664.610 548.740 665.010 549.140 ;
    END
  END s_axil_rdata[27]
  PIN s_axil_rdata[28]
    DIRECTION OUTPUT ;
    USE SIGNAL ;
    ANTENNADIFFAREA 0.708600 ;
    PORT
      LAYER Metal3 ;
        RECT 664.610 564.700 665.010 565.100 ;
    END
  END s_axil_rdata[28]
  PIN s_axil_rdata[29]
    DIRECTION OUTPUT ;
    USE SIGNAL ;
    ANTENNADIFFAREA 0.708600 ;
    PORT
      LAYER Metal3 ;
        RECT 664.610 580.660 665.010 581.060 ;
    END
  END s_axil_rdata[29]
  PIN s_axil_rdata[2]
    DIRECTION OUTPUT ;
    USE SIGNAL ;
    ANTENNADIFFAREA 0.708600 ;
    PORT
      LAYER Metal3 ;
        RECT 664.610 149.740 665.010 150.140 ;
    END
  END s_axil_rdata[2]
  PIN s_axil_rdata[30]
    DIRECTION OUTPUT ;
    USE SIGNAL ;
    ANTENNADIFFAREA 0.708600 ;
    PORT
      LAYER Metal3 ;
        RECT 664.610 596.620 665.010 597.020 ;
    END
  END s_axil_rdata[30]
  PIN s_axil_rdata[31]
    DIRECTION OUTPUT ;
    USE SIGNAL ;
    ANTENNADIFFAREA 0.708600 ;
    PORT
      LAYER Metal3 ;
        RECT 664.610 612.580 665.010 612.980 ;
    END
  END s_axil_rdata[31]
  PIN s_axil_rdata[3]
    DIRECTION OUTPUT ;
    USE SIGNAL ;
    ANTENNADIFFAREA 0.708600 ;
    PORT
      LAYER Metal3 ;
        RECT 664.610 165.700 665.010 166.100 ;
    END
  END s_axil_rdata[3]
  PIN s_axil_rdata[4]
    DIRECTION OUTPUT ;
    USE SIGNAL ;
    ANTENNADIFFAREA 0.708600 ;
    PORT
      LAYER Metal3 ;
        RECT 664.610 181.660 665.010 182.060 ;
    END
  END s_axil_rdata[4]
  PIN s_axil_rdata[5]
    DIRECTION OUTPUT ;
    USE SIGNAL ;
    ANTENNADIFFAREA 0.708600 ;
    PORT
      LAYER Metal3 ;
        RECT 664.610 197.620 665.010 198.020 ;
    END
  END s_axil_rdata[5]
  PIN s_axil_rdata[6]
    DIRECTION OUTPUT ;
    USE SIGNAL ;
    ANTENNADIFFAREA 0.708600 ;
    PORT
      LAYER Metal3 ;
        RECT 664.610 213.580 665.010 213.980 ;
    END
  END s_axil_rdata[6]
  PIN s_axil_rdata[7]
    DIRECTION OUTPUT ;
    USE SIGNAL ;
    ANTENNADIFFAREA 0.708600 ;
    PORT
      LAYER Metal3 ;
        RECT 664.610 229.540 665.010 229.940 ;
    END
  END s_axil_rdata[7]
  PIN s_axil_rdata[8]
    DIRECTION OUTPUT ;
    USE SIGNAL ;
    ANTENNADIFFAREA 0.708600 ;
    PORT
      LAYER Metal3 ;
        RECT 664.610 245.500 665.010 245.900 ;
    END
  END s_axil_rdata[8]
  PIN s_axil_rdata[9]
    DIRECTION OUTPUT ;
    USE SIGNAL ;
    ANTENNADIFFAREA 0.708600 ;
    PORT
      LAYER Metal3 ;
        RECT 664.610 261.460 665.010 261.860 ;
    END
  END s_axil_rdata[9]
  PIN s_axil_rready
    DIRECTION INPUT ;
    USE SIGNAL ;
    ANTENNAGATEAREA 0.180700 ;
    PORT
      LAYER Metal3 ;
        RECT 0.000 638.620 0.400 639.020 ;
    END
  END s_axil_rready
  PIN s_axil_rresp[0]
    DIRECTION OUTPUT ;
    USE SIGNAL ;
    ANTENNADIFFAREA 0.708600 ;
    PORT
      LAYER Metal3 ;
        RECT 664.610 628.540 665.010 628.940 ;
    END
  END s_axil_rresp[0]
  PIN s_axil_rresp[1]
    DIRECTION OUTPUT ;
    USE SIGNAL ;
    ANTENNADIFFAREA 0.708600 ;
    PORT
      LAYER Metal3 ;
        RECT 664.610 644.500 665.010 644.900 ;
    END
  END s_axil_rresp[1]
  PIN s_axil_rvalid
    DIRECTION OUTPUT ;
    USE SIGNAL ;
    ANTENNADIFFAREA 0.708600 ;
    PORT
      LAYER Metal3 ;
        RECT 664.610 660.460 665.010 660.860 ;
    END
  END s_axil_rvalid
  PIN s_axil_wdata[0]
    DIRECTION INPUT ;
    USE SIGNAL ;
    ANTENNAGATEAREA 0.180700 ;
    PORT
      LAYER Metal2 ;
        RECT 415.960 0.000 416.360 0.400 ;
    END
  END s_axil_wdata[0]
  PIN s_axil_wdata[10]
    DIRECTION INPUT ;
    USE SIGNAL ;
    ANTENNAGATEAREA 0.180700 ;
    PORT
      LAYER Metal2 ;
        RECT 473.560 0.000 473.960 0.400 ;
    END
  END s_axil_wdata[10]
  PIN s_axil_wdata[11]
    DIRECTION INPUT ;
    USE SIGNAL ;
    ANTENNAGATEAREA 0.180700 ;
    PORT
      LAYER Metal2 ;
        RECT 479.320 0.000 479.720 0.400 ;
    END
  END s_axil_wdata[11]
  PIN s_axil_wdata[12]
    DIRECTION INPUT ;
    USE SIGNAL ;
    ANTENNAGATEAREA 0.180700 ;
    PORT
      LAYER Metal2 ;
        RECT 485.080 0.000 485.480 0.400 ;
    END
  END s_axil_wdata[12]
  PIN s_axil_wdata[13]
    DIRECTION INPUT ;
    USE SIGNAL ;
    ANTENNAGATEAREA 0.180700 ;
    PORT
      LAYER Metal2 ;
        RECT 490.840 0.000 491.240 0.400 ;
    END
  END s_axil_wdata[13]
  PIN s_axil_wdata[14]
    DIRECTION INPUT ;
    USE SIGNAL ;
    ANTENNAGATEAREA 0.180700 ;
    PORT
      LAYER Metal2 ;
        RECT 496.600 0.000 497.000 0.400 ;
    END
  END s_axil_wdata[14]
  PIN s_axil_wdata[15]
    DIRECTION INPUT ;
    USE SIGNAL ;
    ANTENNAGATEAREA 0.180700 ;
    PORT
      LAYER Metal2 ;
        RECT 502.360 0.000 502.760 0.400 ;
    END
  END s_axil_wdata[15]
  PIN s_axil_wdata[16]
    DIRECTION INPUT ;
    USE SIGNAL ;
    ANTENNAGATEAREA 0.180700 ;
    PORT
      LAYER Metal2 ;
        RECT 508.120 0.000 508.520 0.400 ;
    END
  END s_axil_wdata[16]
  PIN s_axil_wdata[17]
    DIRECTION INPUT ;
    USE SIGNAL ;
    ANTENNAGATEAREA 0.180700 ;
    PORT
      LAYER Metal2 ;
        RECT 513.880 0.000 514.280 0.400 ;
    END
  END s_axil_wdata[17]
  PIN s_axil_wdata[18]
    DIRECTION INPUT ;
    USE SIGNAL ;
    ANTENNAGATEAREA 0.180700 ;
    PORT
      LAYER Metal2 ;
        RECT 519.640 0.000 520.040 0.400 ;
    END
  END s_axil_wdata[18]
  PIN s_axil_wdata[19]
    DIRECTION INPUT ;
    USE SIGNAL ;
    ANTENNAGATEAREA 0.180700 ;
    PORT
      LAYER Metal2 ;
        RECT 525.400 0.000 525.800 0.400 ;
    END
  END s_axil_wdata[19]
  PIN s_axil_wdata[1]
    DIRECTION INPUT ;
    USE SIGNAL ;
    ANTENNAGATEAREA 0.180700 ;
    PORT
      LAYER Metal2 ;
        RECT 421.720 0.000 422.120 0.400 ;
    END
  END s_axil_wdata[1]
  PIN s_axil_wdata[20]
    DIRECTION INPUT ;
    USE SIGNAL ;
    ANTENNAGATEAREA 0.180700 ;
    PORT
      LAYER Metal2 ;
        RECT 531.160 0.000 531.560 0.400 ;
    END
  END s_axil_wdata[20]
  PIN s_axil_wdata[21]
    DIRECTION INPUT ;
    USE SIGNAL ;
    ANTENNAGATEAREA 0.180700 ;
    PORT
      LAYER Metal2 ;
        RECT 536.920 0.000 537.320 0.400 ;
    END
  END s_axil_wdata[21]
  PIN s_axil_wdata[22]
    DIRECTION INPUT ;
    USE SIGNAL ;
    ANTENNAGATEAREA 0.180700 ;
    PORT
      LAYER Metal2 ;
        RECT 542.680 0.000 543.080 0.400 ;
    END
  END s_axil_wdata[22]
  PIN s_axil_wdata[23]
    DIRECTION INPUT ;
    USE SIGNAL ;
    ANTENNAGATEAREA 0.180700 ;
    PORT
      LAYER Metal2 ;
        RECT 548.440 0.000 548.840 0.400 ;
    END
  END s_axil_wdata[23]
  PIN s_axil_wdata[24]
    DIRECTION INPUT ;
    USE SIGNAL ;
    ANTENNAGATEAREA 0.180700 ;
    PORT
      LAYER Metal2 ;
        RECT 554.200 0.000 554.600 0.400 ;
    END
  END s_axil_wdata[24]
  PIN s_axil_wdata[25]
    DIRECTION INPUT ;
    USE SIGNAL ;
    ANTENNAGATEAREA 0.180700 ;
    PORT
      LAYER Metal2 ;
        RECT 559.960 0.000 560.360 0.400 ;
    END
  END s_axil_wdata[25]
  PIN s_axil_wdata[26]
    DIRECTION INPUT ;
    USE SIGNAL ;
    ANTENNAGATEAREA 0.180700 ;
    PORT
      LAYER Metal2 ;
        RECT 565.720 0.000 566.120 0.400 ;
    END
  END s_axil_wdata[26]
  PIN s_axil_wdata[27]
    DIRECTION INPUT ;
    USE SIGNAL ;
    ANTENNAGATEAREA 0.180700 ;
    PORT
      LAYER Metal2 ;
        RECT 571.480 0.000 571.880 0.400 ;
    END
  END s_axil_wdata[27]
  PIN s_axil_wdata[28]
    DIRECTION INPUT ;
    USE SIGNAL ;
    ANTENNAGATEAREA 0.180700 ;
    PORT
      LAYER Metal2 ;
        RECT 577.240 0.000 577.640 0.400 ;
    END
  END s_axil_wdata[28]
  PIN s_axil_wdata[29]
    DIRECTION INPUT ;
    USE SIGNAL ;
    ANTENNAGATEAREA 0.180700 ;
    PORT
      LAYER Metal2 ;
        RECT 583.000 0.000 583.400 0.400 ;
    END
  END s_axil_wdata[29]
  PIN s_axil_wdata[2]
    DIRECTION INPUT ;
    USE SIGNAL ;
    ANTENNAGATEAREA 0.180700 ;
    PORT
      LAYER Metal2 ;
        RECT 427.480 0.000 427.880 0.400 ;
    END
  END s_axil_wdata[2]
  PIN s_axil_wdata[30]
    DIRECTION INPUT ;
    USE SIGNAL ;
    ANTENNAGATEAREA 0.180700 ;
    PORT
      LAYER Metal2 ;
        RECT 588.760 0.000 589.160 0.400 ;
    END
  END s_axil_wdata[30]
  PIN s_axil_wdata[31]
    DIRECTION INPUT ;
    USE SIGNAL ;
    ANTENNAGATEAREA 0.180700 ;
    PORT
      LAYER Metal2 ;
        RECT 594.520 0.000 594.920 0.400 ;
    END
  END s_axil_wdata[31]
  PIN s_axil_wdata[3]
    DIRECTION INPUT ;
    USE SIGNAL ;
    ANTENNAGATEAREA 0.180700 ;
    PORT
      LAYER Metal2 ;
        RECT 433.240 0.000 433.640 0.400 ;
    END
  END s_axil_wdata[3]
  PIN s_axil_wdata[4]
    DIRECTION INPUT ;
    USE SIGNAL ;
    ANTENNAGATEAREA 0.180700 ;
    PORT
      LAYER Metal2 ;
        RECT 439.000 0.000 439.400 0.400 ;
    END
  END s_axil_wdata[4]
  PIN s_axil_wdata[5]
    DIRECTION INPUT ;
    USE SIGNAL ;
    ANTENNAGATEAREA 0.180700 ;
    PORT
      LAYER Metal2 ;
        RECT 444.760 0.000 445.160 0.400 ;
    END
  END s_axil_wdata[5]
  PIN s_axil_wdata[6]
    DIRECTION INPUT ;
    USE SIGNAL ;
    ANTENNAGATEAREA 0.180700 ;
    PORT
      LAYER Metal2 ;
        RECT 450.520 0.000 450.920 0.400 ;
    END
  END s_axil_wdata[6]
  PIN s_axil_wdata[7]
    DIRECTION INPUT ;
    USE SIGNAL ;
    ANTENNAGATEAREA 0.180700 ;
    PORT
      LAYER Metal2 ;
        RECT 456.280 0.000 456.680 0.400 ;
    END
  END s_axil_wdata[7]
  PIN s_axil_wdata[8]
    DIRECTION INPUT ;
    USE SIGNAL ;
    ANTENNAGATEAREA 0.180700 ;
    PORT
      LAYER Metal2 ;
        RECT 462.040 0.000 462.440 0.400 ;
    END
  END s_axil_wdata[8]
  PIN s_axil_wdata[9]
    DIRECTION INPUT ;
    USE SIGNAL ;
    ANTENNAGATEAREA 0.180700 ;
    PORT
      LAYER Metal2 ;
        RECT 467.800 0.000 468.200 0.400 ;
    END
  END s_axil_wdata[9]
  PIN s_axil_wready
    DIRECTION OUTPUT ;
    USE SIGNAL ;
    ANTENNADIFFAREA 0.708600 ;
    PORT
      LAYER Metal3 ;
        RECT 664.610 38.020 665.010 38.420 ;
    END
  END s_axil_wready
  PIN s_axil_wstrb[0]
    DIRECTION INPUT ;
    USE SIGNAL ;
    ANTENNAGATEAREA 0.180700 ;
    PORT
      LAYER Metal2 ;
        RECT 600.280 0.000 600.680 0.400 ;
    END
  END s_axil_wstrb[0]
  PIN s_axil_wstrb[1]
    DIRECTION INPUT ;
    USE SIGNAL ;
    ANTENNAGATEAREA 0.180700 ;
    PORT
      LAYER Metal2 ;
        RECT 606.040 0.000 606.440 0.400 ;
    END
  END s_axil_wstrb[1]
  PIN s_axil_wstrb[2]
    DIRECTION INPUT ;
    USE SIGNAL ;
    ANTENNAGATEAREA 0.180700 ;
    PORT
      LAYER Metal2 ;
        RECT 611.800 0.000 612.200 0.400 ;
    END
  END s_axil_wstrb[2]
  PIN s_axil_wstrb[3]
    DIRECTION INPUT ;
    USE SIGNAL ;
    ANTENNAGATEAREA 0.180700 ;
    PORT
      LAYER Metal2 ;
        RECT 617.560 0.000 617.960 0.400 ;
    END
  END s_axil_wstrb[3]
  PIN s_axil_wvalid
    DIRECTION INPUT ;
    USE SIGNAL ;
    ANTENNAGATEAREA 0.180700 ;
    PORT
      LAYER Metal3 ;
        RECT 0.000 384.100 0.400 384.500 ;
    END
  END s_axil_wvalid
  OBS
      LAYER GatPoly ;
        RECT 5.760 14.970 659.040 665.430 ;
      LAYER Metal1 ;
        RECT 5.760 14.900 659.040 665.500 ;
      LAYER Metal2 ;
        RECT 4.215 683.120 29.830 683.630 ;
        RECT 30.650 683.120 39.430 683.630 ;
        RECT 40.250 683.120 49.030 683.630 ;
        RECT 49.850 683.120 58.630 683.630 ;
        RECT 59.450 683.120 68.230 683.630 ;
        RECT 69.050 683.120 77.830 683.630 ;
        RECT 78.650 683.120 87.430 683.630 ;
        RECT 88.250 683.120 97.030 683.630 ;
        RECT 97.850 683.120 106.630 683.630 ;
        RECT 107.450 683.120 116.230 683.630 ;
        RECT 117.050 683.120 125.830 683.630 ;
        RECT 126.650 683.120 135.430 683.630 ;
        RECT 136.250 683.120 145.030 683.630 ;
        RECT 145.850 683.120 154.630 683.630 ;
        RECT 155.450 683.120 164.230 683.630 ;
        RECT 165.050 683.120 173.830 683.630 ;
        RECT 174.650 683.120 183.430 683.630 ;
        RECT 184.250 683.120 193.030 683.630 ;
        RECT 193.850 683.120 202.630 683.630 ;
        RECT 203.450 683.120 212.230 683.630 ;
        RECT 213.050 683.120 221.830 683.630 ;
        RECT 222.650 683.120 231.430 683.630 ;
        RECT 232.250 683.120 241.030 683.630 ;
        RECT 241.850 683.120 250.630 683.630 ;
        RECT 251.450 683.120 260.230 683.630 ;
        RECT 261.050 683.120 269.830 683.630 ;
        RECT 270.650 683.120 279.430 683.630 ;
        RECT 280.250 683.120 289.030 683.630 ;
        RECT 289.850 683.120 298.630 683.630 ;
        RECT 299.450 683.120 308.230 683.630 ;
        RECT 309.050 683.120 317.830 683.630 ;
        RECT 318.650 683.120 327.430 683.630 ;
        RECT 328.250 683.120 337.030 683.630 ;
        RECT 337.850 683.120 346.630 683.630 ;
        RECT 347.450 683.120 356.230 683.630 ;
        RECT 357.050 683.120 365.830 683.630 ;
        RECT 366.650 683.120 375.430 683.630 ;
        RECT 376.250 683.120 385.030 683.630 ;
        RECT 385.850 683.120 394.630 683.630 ;
        RECT 395.450 683.120 404.230 683.630 ;
        RECT 405.050 683.120 413.830 683.630 ;
        RECT 414.650 683.120 423.430 683.630 ;
        RECT 424.250 683.120 433.030 683.630 ;
        RECT 433.850 683.120 442.630 683.630 ;
        RECT 443.450 683.120 452.230 683.630 ;
        RECT 453.050 683.120 461.830 683.630 ;
        RECT 462.650 683.120 471.430 683.630 ;
        RECT 472.250 683.120 481.030 683.630 ;
        RECT 481.850 683.120 490.630 683.630 ;
        RECT 491.450 683.120 500.230 683.630 ;
        RECT 501.050 683.120 509.830 683.630 ;
        RECT 510.650 683.120 519.430 683.630 ;
        RECT 520.250 683.120 529.030 683.630 ;
        RECT 529.850 683.120 538.630 683.630 ;
        RECT 539.450 683.120 548.230 683.630 ;
        RECT 549.050 683.120 557.830 683.630 ;
        RECT 558.650 683.120 567.430 683.630 ;
        RECT 568.250 683.120 577.030 683.630 ;
        RECT 577.850 683.120 586.630 683.630 ;
        RECT 587.450 683.120 596.230 683.630 ;
        RECT 597.050 683.120 605.830 683.630 ;
        RECT 606.650 683.120 615.430 683.630 ;
        RECT 616.250 683.120 625.030 683.630 ;
        RECT 625.850 683.120 634.630 683.630 ;
        RECT 635.450 683.120 658.665 683.630 ;
        RECT 4.215 0.610 658.665 683.120 ;
        RECT 4.215 0.100 47.110 0.610 ;
        RECT 47.930 0.100 52.870 0.610 ;
        RECT 53.690 0.100 58.630 0.610 ;
        RECT 59.450 0.100 64.390 0.610 ;
        RECT 65.210 0.100 70.150 0.610 ;
        RECT 70.970 0.100 75.910 0.610 ;
        RECT 76.730 0.100 81.670 0.610 ;
        RECT 82.490 0.100 87.430 0.610 ;
        RECT 88.250 0.100 93.190 0.610 ;
        RECT 94.010 0.100 98.950 0.610 ;
        RECT 99.770 0.100 104.710 0.610 ;
        RECT 105.530 0.100 110.470 0.610 ;
        RECT 111.290 0.100 116.230 0.610 ;
        RECT 117.050 0.100 121.990 0.610 ;
        RECT 122.810 0.100 127.750 0.610 ;
        RECT 128.570 0.100 133.510 0.610 ;
        RECT 134.330 0.100 139.270 0.610 ;
        RECT 140.090 0.100 145.030 0.610 ;
        RECT 145.850 0.100 150.790 0.610 ;
        RECT 151.610 0.100 156.550 0.610 ;
        RECT 157.370 0.100 162.310 0.610 ;
        RECT 163.130 0.100 168.070 0.610 ;
        RECT 168.890 0.100 173.830 0.610 ;
        RECT 174.650 0.100 179.590 0.610 ;
        RECT 180.410 0.100 185.350 0.610 ;
        RECT 186.170 0.100 191.110 0.610 ;
        RECT 191.930 0.100 196.870 0.610 ;
        RECT 197.690 0.100 202.630 0.610 ;
        RECT 203.450 0.100 208.390 0.610 ;
        RECT 209.210 0.100 214.150 0.610 ;
        RECT 214.970 0.100 219.910 0.610 ;
        RECT 220.730 0.100 225.670 0.610 ;
        RECT 226.490 0.100 231.430 0.610 ;
        RECT 232.250 0.100 237.190 0.610 ;
        RECT 238.010 0.100 242.950 0.610 ;
        RECT 243.770 0.100 248.710 0.610 ;
        RECT 249.530 0.100 254.470 0.610 ;
        RECT 255.290 0.100 260.230 0.610 ;
        RECT 261.050 0.100 265.990 0.610 ;
        RECT 266.810 0.100 271.750 0.610 ;
        RECT 272.570 0.100 277.510 0.610 ;
        RECT 278.330 0.100 283.270 0.610 ;
        RECT 284.090 0.100 289.030 0.610 ;
        RECT 289.850 0.100 294.790 0.610 ;
        RECT 295.610 0.100 300.550 0.610 ;
        RECT 301.370 0.100 306.310 0.610 ;
        RECT 307.130 0.100 312.070 0.610 ;
        RECT 312.890 0.100 317.830 0.610 ;
        RECT 318.650 0.100 323.590 0.610 ;
        RECT 324.410 0.100 329.350 0.610 ;
        RECT 330.170 0.100 335.110 0.610 ;
        RECT 335.930 0.100 340.870 0.610 ;
        RECT 341.690 0.100 346.630 0.610 ;
        RECT 347.450 0.100 352.390 0.610 ;
        RECT 353.210 0.100 358.150 0.610 ;
        RECT 358.970 0.100 363.910 0.610 ;
        RECT 364.730 0.100 369.670 0.610 ;
        RECT 370.490 0.100 375.430 0.610 ;
        RECT 376.250 0.100 381.190 0.610 ;
        RECT 382.010 0.100 386.950 0.610 ;
        RECT 387.770 0.100 392.710 0.610 ;
        RECT 393.530 0.100 398.470 0.610 ;
        RECT 399.290 0.100 404.230 0.610 ;
        RECT 405.050 0.100 409.990 0.610 ;
        RECT 410.810 0.100 415.750 0.610 ;
        RECT 416.570 0.100 421.510 0.610 ;
        RECT 422.330 0.100 427.270 0.610 ;
        RECT 428.090 0.100 433.030 0.610 ;
        RECT 433.850 0.100 438.790 0.610 ;
        RECT 439.610 0.100 444.550 0.610 ;
        RECT 445.370 0.100 450.310 0.610 ;
        RECT 451.130 0.100 456.070 0.610 ;
        RECT 456.890 0.100 461.830 0.610 ;
        RECT 462.650 0.100 467.590 0.610 ;
        RECT 468.410 0.100 473.350 0.610 ;
        RECT 474.170 0.100 479.110 0.610 ;
        RECT 479.930 0.100 484.870 0.610 ;
        RECT 485.690 0.100 490.630 0.610 ;
        RECT 491.450 0.100 496.390 0.610 ;
        RECT 497.210 0.100 502.150 0.610 ;
        RECT 502.970 0.100 507.910 0.610 ;
        RECT 508.730 0.100 513.670 0.610 ;
        RECT 514.490 0.100 519.430 0.610 ;
        RECT 520.250 0.100 525.190 0.610 ;
        RECT 526.010 0.100 530.950 0.610 ;
        RECT 531.770 0.100 536.710 0.610 ;
        RECT 537.530 0.100 542.470 0.610 ;
        RECT 543.290 0.100 548.230 0.610 ;
        RECT 549.050 0.100 553.990 0.610 ;
        RECT 554.810 0.100 559.750 0.610 ;
        RECT 560.570 0.100 565.510 0.610 ;
        RECT 566.330 0.100 571.270 0.610 ;
        RECT 572.090 0.100 577.030 0.610 ;
        RECT 577.850 0.100 582.790 0.610 ;
        RECT 583.610 0.100 588.550 0.610 ;
        RECT 589.370 0.100 594.310 0.610 ;
        RECT 595.130 0.100 600.070 0.610 ;
        RECT 600.890 0.100 605.830 0.610 ;
        RECT 606.650 0.100 611.590 0.610 ;
        RECT 612.410 0.100 617.350 0.610 ;
        RECT 618.170 0.100 658.665 0.610 ;
      LAYER Metal3 ;
        RECT 0.400 661.070 664.610 669.580 ;
        RECT 0.400 660.250 664.400 661.070 ;
        RECT 0.400 645.110 664.610 660.250 ;
        RECT 0.400 644.290 664.400 645.110 ;
        RECT 0.400 639.230 664.610 644.290 ;
        RECT 0.610 638.410 664.610 639.230 ;
        RECT 0.400 629.150 664.610 638.410 ;
        RECT 0.400 628.330 664.400 629.150 ;
        RECT 0.400 613.190 664.610 628.330 ;
        RECT 0.400 612.370 664.400 613.190 ;
        RECT 0.400 597.230 664.610 612.370 ;
        RECT 0.400 596.410 664.400 597.230 ;
        RECT 0.400 581.270 664.610 596.410 ;
        RECT 0.400 580.450 664.400 581.270 ;
        RECT 0.400 565.310 664.610 580.450 ;
        RECT 0.400 564.490 664.400 565.310 ;
        RECT 0.400 554.390 664.610 564.490 ;
        RECT 0.610 553.570 664.610 554.390 ;
        RECT 0.400 549.350 664.610 553.570 ;
        RECT 0.400 548.530 664.400 549.350 ;
        RECT 0.400 533.390 664.610 548.530 ;
        RECT 0.400 532.570 664.400 533.390 ;
        RECT 0.400 517.430 664.610 532.570 ;
        RECT 0.400 516.610 664.400 517.430 ;
        RECT 0.400 501.470 664.610 516.610 ;
        RECT 0.400 500.650 664.400 501.470 ;
        RECT 0.400 485.510 664.610 500.650 ;
        RECT 0.400 484.690 664.400 485.510 ;
        RECT 0.400 469.550 664.610 484.690 ;
        RECT 0.610 468.730 664.400 469.550 ;
        RECT 0.400 453.590 664.610 468.730 ;
        RECT 0.400 452.770 664.400 453.590 ;
        RECT 0.400 437.630 664.610 452.770 ;
        RECT 0.400 436.810 664.400 437.630 ;
        RECT 0.400 421.670 664.610 436.810 ;
        RECT 0.400 420.850 664.400 421.670 ;
        RECT 0.400 405.710 664.610 420.850 ;
        RECT 0.400 404.890 664.400 405.710 ;
        RECT 0.400 389.750 664.610 404.890 ;
        RECT 0.400 388.930 664.400 389.750 ;
        RECT 0.400 384.710 664.610 388.930 ;
        RECT 0.610 383.890 664.610 384.710 ;
        RECT 0.400 373.790 664.610 383.890 ;
        RECT 0.400 372.970 664.400 373.790 ;
        RECT 0.400 357.830 664.610 372.970 ;
        RECT 0.400 357.010 664.400 357.830 ;
        RECT 0.400 341.870 664.610 357.010 ;
        RECT 0.400 341.050 664.400 341.870 ;
        RECT 0.400 325.910 664.610 341.050 ;
        RECT 0.400 325.090 664.400 325.910 ;
        RECT 0.400 309.950 664.610 325.090 ;
        RECT 0.400 309.130 664.400 309.950 ;
        RECT 0.400 299.870 664.610 309.130 ;
        RECT 0.610 299.050 664.610 299.870 ;
        RECT 0.400 293.990 664.610 299.050 ;
        RECT 0.400 293.170 664.400 293.990 ;
        RECT 0.400 278.030 664.610 293.170 ;
        RECT 0.400 277.210 664.400 278.030 ;
        RECT 0.400 262.070 664.610 277.210 ;
        RECT 0.400 261.250 664.400 262.070 ;
        RECT 0.400 246.110 664.610 261.250 ;
        RECT 0.400 245.290 664.400 246.110 ;
        RECT 0.400 230.150 664.610 245.290 ;
        RECT 0.400 229.330 664.400 230.150 ;
        RECT 0.400 215.030 664.610 229.330 ;
        RECT 0.610 214.210 664.610 215.030 ;
        RECT 0.400 214.190 664.610 214.210 ;
        RECT 0.400 213.370 664.400 214.190 ;
        RECT 0.400 198.230 664.610 213.370 ;
        RECT 0.400 197.410 664.400 198.230 ;
        RECT 0.400 182.270 664.610 197.410 ;
        RECT 0.400 181.450 664.400 182.270 ;
        RECT 0.400 166.310 664.610 181.450 ;
        RECT 0.400 165.490 664.400 166.310 ;
        RECT 0.400 150.350 664.610 165.490 ;
        RECT 0.400 149.530 664.400 150.350 ;
        RECT 0.400 134.390 664.610 149.530 ;
        RECT 0.400 133.570 664.400 134.390 ;
        RECT 0.400 130.190 664.610 133.570 ;
        RECT 0.610 129.370 664.610 130.190 ;
        RECT 0.400 118.430 664.610 129.370 ;
        RECT 0.400 117.610 664.400 118.430 ;
        RECT 0.400 102.470 664.610 117.610 ;
        RECT 0.400 101.650 664.400 102.470 ;
        RECT 0.400 86.510 664.610 101.650 ;
        RECT 0.400 85.690 664.400 86.510 ;
        RECT 0.400 70.550 664.610 85.690 ;
        RECT 0.400 69.730 664.400 70.550 ;
        RECT 0.400 54.590 664.610 69.730 ;
        RECT 0.400 53.770 664.400 54.590 ;
        RECT 0.400 45.350 664.610 53.770 ;
        RECT 0.610 44.530 664.610 45.350 ;
        RECT 0.400 38.630 664.610 44.530 ;
        RECT 0.400 37.810 664.400 38.630 ;
        RECT 0.400 22.670 664.610 37.810 ;
        RECT 0.400 21.850 664.400 22.670 ;
        RECT 0.400 7.040 664.610 21.850 ;
      LAYER Metal4 ;
        RECT 18.440 14.975 657.700 665.425 ;
      LAYER Metal5 ;
        RECT 18.395 14.810 631.325 665.590 ;
  END
END ram_macro
END LIBRARY

